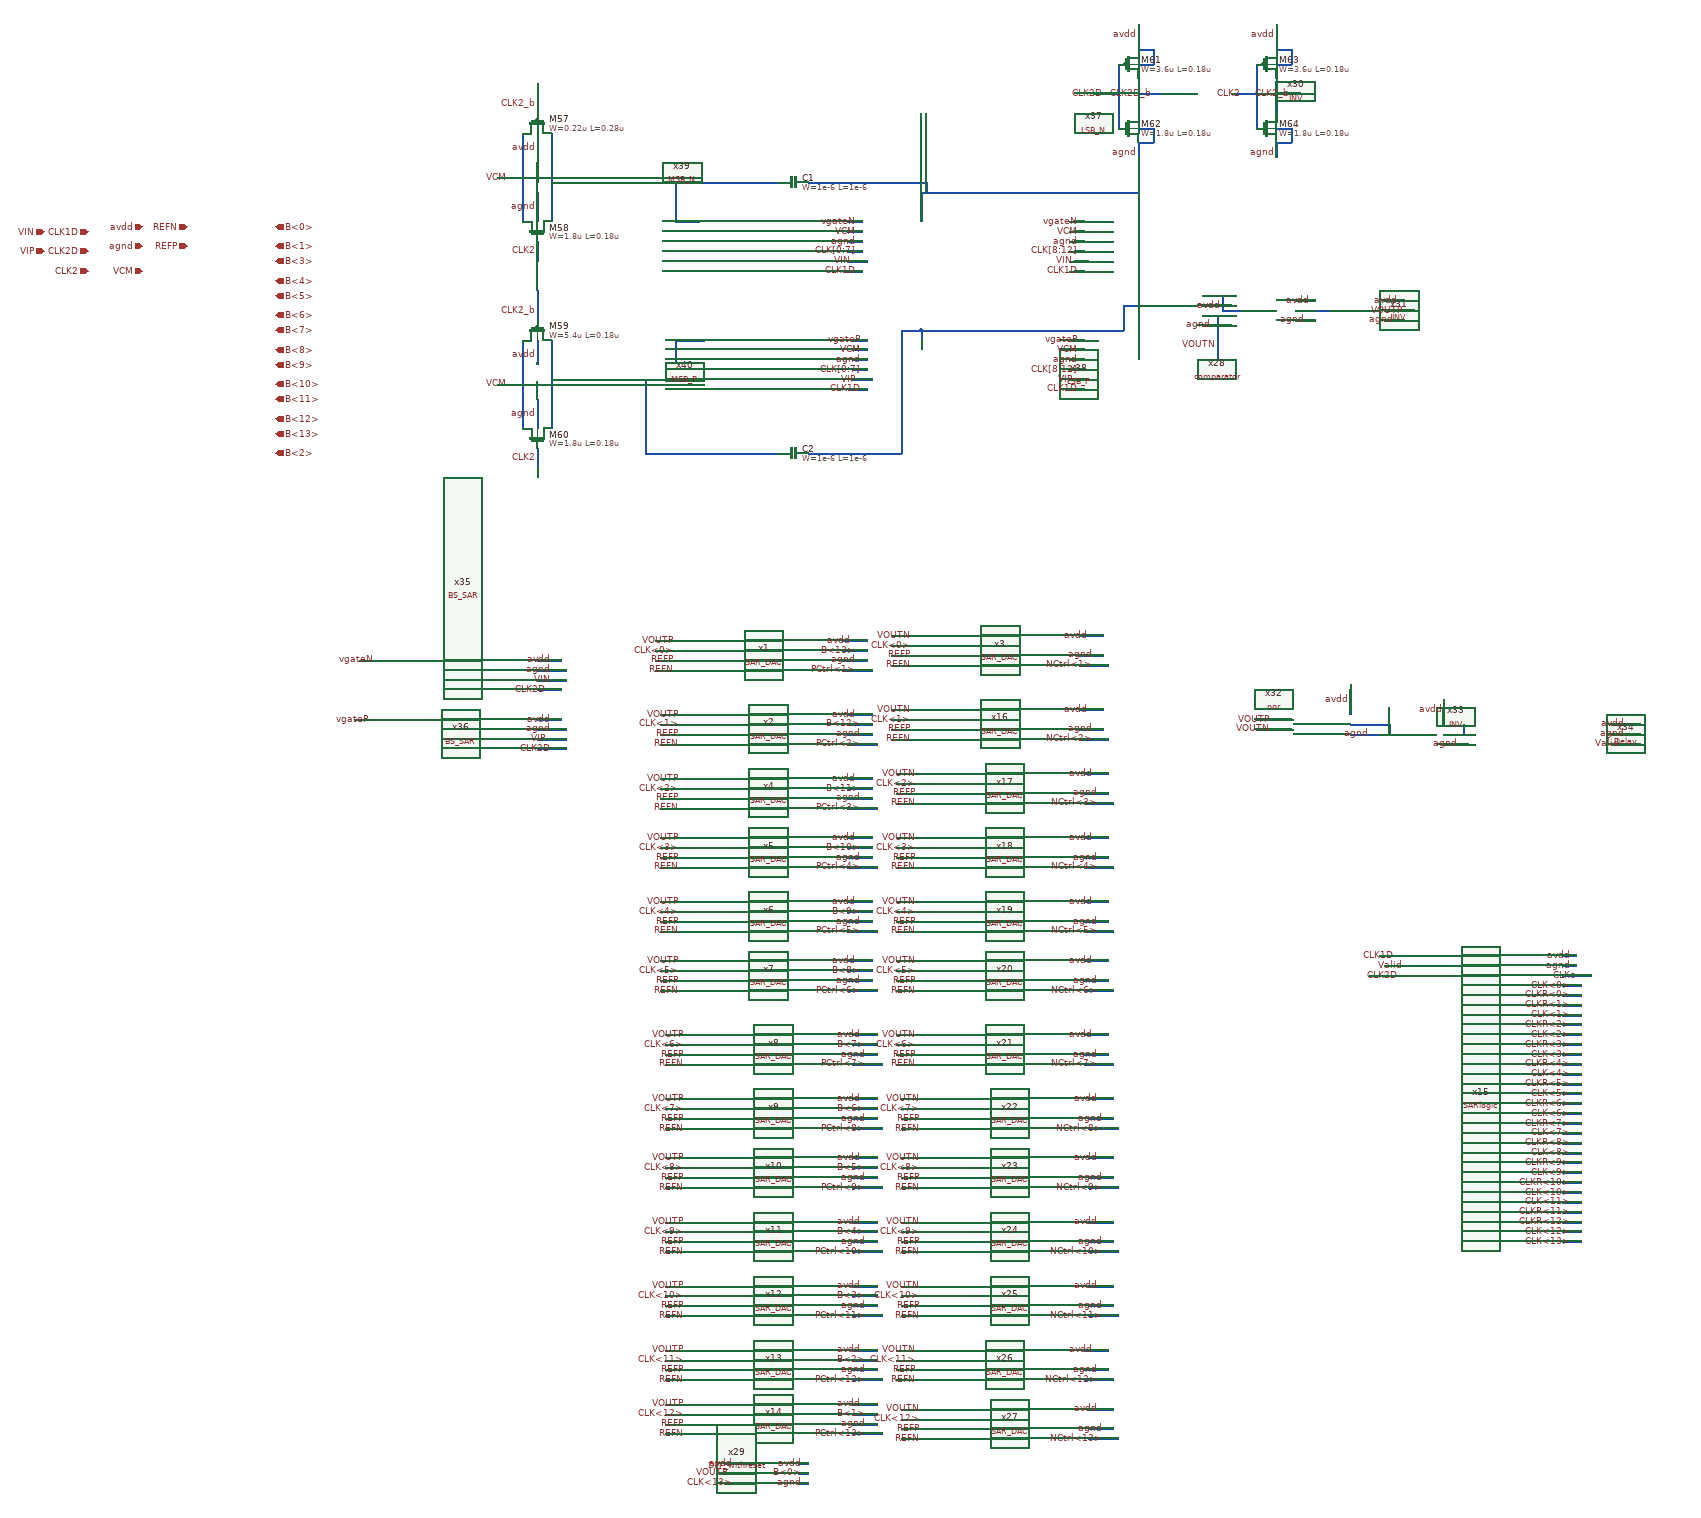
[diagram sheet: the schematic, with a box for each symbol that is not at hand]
v {xschem version=3.1.0 file_version=1.2
}
G {}
K {}
V {}
S {}
E {}
N 660 -670 710 -670 {
lab=avdd}
N 660 -630 710 -630 {
lab=agnd}
N 660 -610 720 -610 {
lab=PCtrl}
N 660 -650 710 -650 {
lab=B<13>}
N 280 -670 360 -670 {
lab=VOUTP}
N 280 -650 360 -650 {
lab=CLK<0>}
N 280 -630 360 -630 {
lab=REFP}
N 280 -610 360 -610 {
lab=REFN}
N 670 -520 720 -520 {
lab=avdd}
N 670 -480 720 -480 {
lab=agnd}
N 670 -460 730 -460 {
lab=PCtrl}
N 670 -500 720 -500 {
lab=B<12>}
N 290 -520 370 -520 {
lab=VOUTP}
N 290 -500 370 -500 {
lab=CLK<1>}
N 290 -480 370 -480 {
lab=REFP}
N 290 -460 370 -460 {
lab=REFN}
N 670 -390 720 -390 {
lab=avdd}
N 670 -350 720 -350 {
lab=agnd}
N 670 -330 730 -330 {
lab=PCtrl}
N 670 -370 720 -370 {
lab=B<11>}
N 290 -390 370 -390 {
lab=VOUTP}
N 290 -370 370 -370 {
lab=CLK<2>}
N 290 -350 370 -350 {
lab=REFP}
N 290 -330 370 -330 {
lab=REFN}
N 670 -270 720 -270 {
lab=avdd}
N 670 -230 720 -230 {
lab=agnd}
N 670 -210 730 -210 {
lab=PCtrl}
N 670 -250 720 -250 {
lab=B<10>}
N 290 -270 370 -270 {
lab=VOUTP}
N 290 -250 370 -250 {
lab=CLK<3>}
N 290 -230 370 -230 {
lab=REFP}
N 290 -210 370 -210 {
lab=REFN}
N 670 -140 720 -140 {
lab=avdd}
N 670 -100 720 -100 {
lab=agnd}
N 670 -80 730 -80 {
lab=PCtrl}
N 670 -120 720 -120 {
lab=B<9>}
N 290 -140 370 -140 {
lab=VOUTP}
N 290 -120 370 -120 {
lab=CLK<4>}
N 290 -100 370 -100 {
lab=REFP}
N 290 -80 370 -80 {
lab=REFN}
N 670 -20 720 -20 {
lab=avdd}
N 670 20 720 20 {
lab=agnd}
N 670 40 730 40 {
lab=PCtrl}
N 670 0 720 0 {
lab=B<8>}
N 290 -20 370 -20 {
lab=VOUTP}
N 290 0 370 0 {
lab=CLK<5>}
N 290 20 370 20 {
lab=REFP}
N 290 40 370 40 {
lab=REFN}
N 680 130 730 130 {
lab=avdd}
N 680 170 730 170 {
lab=agnd}
N 680 190 740 190 {
lab=PCtrl}
N 680 150 730 150 {
lab=B<7>}
N 300 130 380 130 {
lab=VOUTP}
N 300 150 380 150 {
lab=CLK<6>}
N 300 170 380 170 {
lab=REFP}
N 300 190 380 190 {
lab=REFN}
N 680 260 730 260 {
lab=avdd}
N 680 300 730 300 {
lab=agnd}
N 680 320 740 320 {
lab=PCtrl}
N 680 280 730 280 {
lab=B<6>}
N 300 260 380 260 {
lab=VOUTP}
N 300 280 380 280 {
lab=CLK<7>}
N 300 300 380 300 {
lab=REFP}
N 300 320 380 320 {
lab=REFN}
N 680 380 730 380 {
lab=avdd}
N 680 420 730 420 {
lab=agnd}
N 680 440 740 440 {
lab=PCtrl}
N 680 400 730 400 {
lab=B<5>}
N 300 380 380 380 {
lab=VOUTP}
N 300 400 380 400 {
lab=CLK<8>}
N 300 420 380 420 {
lab=REFP}
N 300 440 380 440 {
lab=REFN}
N 680 510 730 510 {
lab=avdd}
N 680 550 730 550 {
lab=agnd}
N 680 570 740 570 {
lab=PCtrl}
N 680 530 730 530 {
lab=B<4>}
N 300 510 380 510 {
lab=VOUTP}
N 300 530 380 530 {
lab=CLK<9>}
N 300 550 380 550 {
lab=REFP}
N 300 570 380 570 {
lab=REFN}
N 680 640 730 640 {
lab=avdd}
N 680 680 730 680 {
lab=agnd}
N 680 700 740 700 {
lab=PCtrl}
N 680 660 730 660 {
lab=B<3>}
N 300 640 380 640 {
lab=VOUTP}
N 300 660 380 660 {
lab=CLK<10>}
N 300 680 380 680 {
lab=REFP}
N 300 700 380 700 {
lab=REFN}
N 680 770 730 770 {
lab=avdd}
N 680 810 730 810 {
lab=agnd}
N 680 830 740 830 {
lab=PCtrl}
N 680 790 730 790 {
lab=B<2>}
N 300 770 380 770 {
lab=VOUTP}
N 300 790 380 790 {
lab=CLK<11>}
N 300 810 380 810 {
lab=REFP}
N 300 830 380 830 {
lab=REFN}
N 680 880 730 880 {
lab=avdd}
N 680 920 730 920 {
lab=agnd}
N 680 940 740 940 {
lab=PCtrl}
N 680 900 730 900 {
lab=B<1>}
N 300 880 380 880 {
lab=VOUTP}
N 300 900 380 900 {
lab=CLK<12>}
N 300 920 380 920 {
lab=REFP}
N 300 940 380 940 {
lab=REFN}
N 1140 -680 1190 -680 {
lab=avdd}
N 1140 -640 1190 -640 {
lab=agnd}
N 1140 -620 1200 -620 {
lab=NCtrl}
N 760 -680 840 -680 {
lab=VOUTN}
N 760 -660 840 -660 {
lab=CLK<0>}
N 760 -640 840 -640 {
lab=REFP}
N 760 -620 840 -620 {
lab=REFN}
N 1140 -530 1190 -530 {
lab=avdd}
N 1140 -490 1190 -490 {
lab=agnd}
N 1140 -470 1200 -470 {
lab=NCtrl}
N 760 -530 840 -530 {
lab=VOUTN}
N 760 -510 840 -510 {
lab=CLK<0>}
N 760 -490 840 -490 {
lab=REFP}
N 760 -470 840 -470 {
lab=REFN}
N 1150 -400 1200 -400 {
lab=avdd}
N 1150 -360 1200 -360 {
lab=agnd}
N 1150 -340 1210 -340 {
lab=NCtrl}
N 770 -400 850 -400 {
lab=VOUTN}
N 770 -380 850 -380 {
lab=CLK<0>}
N 770 -360 850 -360 {
lab=REFP}
N 770 -340 850 -340 {
lab=REFN}
N 1150 -270 1200 -270 {
lab=avdd}
N 1150 -230 1200 -230 {
lab=agnd}
N 1150 -210 1210 -210 {
lab=NCtrl}
N 770 -270 850 -270 {
lab=VOUTN}
N 770 -250 850 -250 {
lab=CLK<0>}
N 770 -230 850 -230 {
lab=REFP}
N 770 -210 850 -210 {
lab=REFN}
N 1150 -140 1200 -140 {
lab=avdd}
N 1150 -100 1200 -100 {
lab=agnd}
N 1150 -80 1210 -80 {
lab=NCtrl}
N 770 -140 850 -140 {
lab=VOUTN}
N 770 -120 850 -120 {
lab=CLK<0>}
N 770 -100 850 -100 {
lab=REFP}
N 770 -80 850 -80 {
lab=REFN}
N 1150 -20 1200 -20 {
lab=avdd}
N 1150 20 1200 20 {
lab=agnd}
N 1150 40 1210 40 {
lab=NCtrl}
N 770 -20 850 -20 {
lab=VOUTN}
N 770 0 850 0 {
lab=CLK<0>}
N 770 20 850 20 {
lab=REFP}
N 770 40 850 40 {
lab=REFN}
N 1150 130 1200 130 {
lab=avdd}
N 1150 170 1200 170 {
lab=agnd}
N 1150 190 1210 190 {
lab=NCtrl}
N 770 130 850 130 {
lab=VOUTN}
N 770 150 850 150 {
lab=CLK<0>}
N 770 170 850 170 {
lab=REFP}
N 770 190 850 190 {
lab=REFN}
N 1160 260 1210 260 {
lab=avdd}
N 1160 300 1210 300 {
lab=agnd}
N 1160 320 1220 320 {
lab=NCtrl}
N 780 260 860 260 {
lab=VOUTN}
N 780 280 860 280 {
lab=CLK<0>}
N 780 300 860 300 {
lab=REFP}
N 780 320 860 320 {
lab=REFN}
N 1160 380 1210 380 {
lab=avdd}
N 1160 420 1210 420 {
lab=agnd}
N 1160 440 1220 440 {
lab=NCtrl}
N 780 380 860 380 {
lab=VOUTN}
N 780 400 860 400 {
lab=CLK<0>}
N 780 420 860 420 {
lab=REFP}
N 780 440 860 440 {
lab=REFN}
N 1160 510 1210 510 {
lab=avdd}
N 1160 550 1210 550 {
lab=agnd}
N 1160 570 1220 570 {
lab=NCtrl}
N 780 510 860 510 {
lab=VOUTN}
N 780 530 860 530 {
lab=CLK<0>}
N 780 550 860 550 {
lab=REFP}
N 780 570 860 570 {
lab=REFN}
N 1160 640 1210 640 {
lab=avdd}
N 1160 680 1210 680 {
lab=agnd}
N 1160 700 1220 700 {
lab=NCtrl}
N 780 640 860 640 {
lab=VOUTN}
N 780 660 860 660 {
lab=CLK<0>}
N 780 680 860 680 {
lab=REFP}
N 780 700 860 700 {
lab=REFN}
N 1150 770 1200 770 {
lab=avdd}
N 1150 810 1200 810 {
lab=agnd}
N 1150 830 1210 830 {
lab=NCtrl}
N 770 770 850 770 {
lab=VOUTN}
N 770 790 850 790 {
lab=CLK<0>}
N 770 810 850 810 {
lab=REFP}
N 770 830 850 830 {
lab=REFN}
N 1160 890 1210 890 {
lab=avdd}
N 1160 930 1210 930 {
lab=agnd}
N 1160 950 1220 950 {
lab=NCtrl}
N 780 890 860 890 {
lab=VOUTN}
N 780 910 860 910 {
lab=CLK<0>}
N 780 930 860 930 {
lab=REFP}
N 780 950 860 950 {
lab=REFN}
N 420 1000 460 1000 {}
N 410 1020 460 1020 {}
N 420 1040 460 1040 {}
N 570 1000 590 1000 {}
N 570 1040 590 1040 {}
N 570 1020 590 1020 {}
N 2120 -30 2150 -30 {}
N 2120 -10 2150 -10 {}
N 1580 -1360 1620 -1360 {}
N 1580 -1320 1620 -1320 {}
N 1760 -1360 1800 -1360 {}
N 1760 -1320 1800 -1320 {}
N 1580 -1340 1650 -1340 {}
N 1390 -1350 1450 -1350 {}
N 1390 -1310 1450 -1310 {}
N 1390 -1330 1420 -1330 {}
N 1420 -1330 1420 -1240 {}
N 1390 -1370 1430 -1370 {}
N 1430 -1370 1430 -1340 {}
N 1430 -1340 1470 -1340 {}
N 1760 -1340 1820 -1340 {}
N 1690 -500 1770 -500 {}
N 1770 -500 1770 -480 {}
N 1880 -480 1920 -480 {}
N 1920 -500 1920 -480 {}
N 1690 -580 1690 -520 {}
N 1690 -480 1750 -480 {}
N 2220 -500 2280 -500 {}
N 2220 -480 2280 -480 {}
N 2220 -460 2280 -460 {}
N 1880 -550 1880 -500 {}
N 1880 -460 1930 -460 {}
N 1760 -10 1830 -10 {}
N 1750 -30 1830 -30 {}
N 1730 10 1830 10 {}
N 2120 10 2180 10 {}
N 40 -610 100 -610 {}
N 40 -630 90 -630 {}
N 40 -490 100 -490 {}
N 40 -510 90 -510 {}
N 40 -570 90 -570 {}
N 40 -450 100 -450 {}
N 40 -590 100 -590 {}
N 40 -470 100 -470 {}
N -320 -630 -260 -630 {}
N -330 -510 -260 -510 {}
N 1500 -510 1570 -510 {}
N 1500 -490 1570 -490 {}
N 70 -1700 70 -1520 {}
N 10 -1700 10 -1520 {}
N 40 -1700 40 -1650 {}
N 40 -1580 40 -1520 {}
N -40 -1610 10 -1610 {}
N 40 -1480 40 -1440 {}
N 40 -1800 40 -1740 {}
N 70 -1280 70 -1100 {}
N 10 -1280 10 -1100 {}
N 40 -1280 40 -1230 {}
N 40 -1160 40 -1100 {}
N -40 -1190 10 -1190 {}
N 40 -1060 40 -1020 {}
N 40 -1380 40 -1320 {}
N 70 -1200 320 -1200 {}
N 70 -1600 320 -1600 {}
N 1260 -1810 1260 -1740 {}
N 1220 -1840 1220 -1710 {}
N 1260 -1710 1290 -1710 {}
N 1290 -1710 1290 -1680 {}
N 1260 -1680 1290 -1680 {}
N 1260 -1680 1260 -1650 {}
N 1260 -1840 1290 -1840 {}
N 1290 -1870 1290 -1840 {}
N 1260 -1870 1290 -1870 {}
N 1260 -1920 1260 -1870 {}
N 1170 -1780 1220 -1780 {}
N 1260 -1780 1310 -1780 {}
N 1540 -1810 1540 -1740 {}
N 1500 -1840 1500 -1710 {}
N 1540 -1710 1570 -1710 {}
N 1570 -1710 1570 -1680 {}
N 1540 -1680 1570 -1680 {}
N 1540 -1680 1540 -1650 {}
N 1540 -1840 1570 -1840 {}
N 1570 -1870 1570 -1840 {}
N 1540 -1870 1570 -1870 {}
N 1540 -1920 1540 -1870 {}
N 1450 -1780 1500 -1780 {}
N 1540 -1780 1590 -1780 {}
N 2120 30 2160 30 {}
N 2120 50 2160 50 {}
N 2120 70 2160 70 {}
N 2120 90 2160 90 {}
N 2120 110 2160 110 {}
N 2120 130 2160 130 {}
N 2120 150 2160 150 {}
N 2120 170 2160 170 {}
N 2120 190 2160 190 {}
N 2120 210 2160 210 {}
N 2120 230 2160 230 {}
N 2120 250 2160 250 {}
N 2120 270 2160 270 {}
N 2120 290 2160 290 {}
N 2120 310 2160 310 {}
N 2120 330 2160 330 {}
N 2120 350 2160 350 {}
N 2120 370 2160 370 {}
N 2120 390 2160 390 {}
N 2120 410 2160 410 {}
N 2120 430 2160 430 {}
N 2120 450 2160 450 {}
N 2120 470 2160 470 {}
N 2120 490 2160 490 {}
N 2120 510 2160 510 {}
N 2120 530 2160 530 {}
N 2120 550 2160 550 {}
N 670 -1440 710 -1440 {}
N 670 -1500 700 -1500 {}
N 670 -1520 700 -1520 {}
N 670 -1480 700 -1480 {}
N 670 -1460 700 -1460 {}
N 670 -1420 700 -1420 {}
N 680 -1200 720 -1200 {}
N 680 -1260 710 -1260 {}
N 680 -1280 710 -1280 {}
N 680 -1240 710 -1240 {}
N 680 -1220 710 -1220 {}
N 680 -1180 710 -1180 {}
N 320 -1600 320 -1520 {}
N 320 -1520 370 -1520 {}
N 320 -1280 320 -1200 {}
N 320 -1280 380 -1280 {}
N 820 -1580 820 -1520 {}
N 820 -1580 1260 -1580 {}
N 1260 -1580 1260 -1370 {}
N 820 -1300 820 -1280 {}
N 820 -1300 1230 -1300 {}
N 1230 -1350 1230 -1300 {}
N 1230 -1350 1260 -1350 {}
N 1120 -1200 1160 -1200 {}
N 1120 -1260 1150 -1260 {}
N 1120 -1280 1150 -1280 {}
N 1120 -1240 1150 -1240 {}
N 1120 -1220 1150 -1220 {}
N 1120 -1180 1150 -1180 {}
N 1120 -1440 1160 -1440 {}
N 1120 -1500 1150 -1500 {}
N 1120 -1520 1150 -1520 {}
N 1120 -1480 1150 -1480 {}
N 1120 -1460 1150 -1460 {}
N 1120 -1420 1150 -1420 {}
N 260 -1200 260 -1050 {}
N 260 -1050 530 -1050 {}
N 780 -1300 780 -1050 {}
N 780 -1300 820 -1300 {}
N 320 -1600 530 -1600 {}
N 590 -1600 830 -1600 {}
N 830 -1600 830 -1580 {}
N 590 -1050 780 -1050 {}
C {SAR_DAC.sym} 510 -640 0 0 {name=x1}
C {lab_pin.sym} 320 -630 0 0 {name=p1 sig_type=std_logic lab=REFP}
C {lab_pin.sym} 320 -610 0 0 {name=p2 sig_type=std_logic lab=REFN}
C {lab_pin.sym} 320 -650 0 0 {name=p3 sig_type=std_logic lab=CLK<0>}
C {lab_pin.sym} 320 -670 0 0 {name=p4 sig_type=std_logic lab=VOUTP}
C {lab_pin.sym} 690 -610 0 0 {name=p5 sig_type=std_logic lab=PCtrl<1>}
C {lab_pin.sym} 690 -630 0 0 {name=p6 sig_type=std_logic lab=agnd}
C {lab_pin.sym} 680 -670 0 0 {name=p7 sig_type=std_logic lab=avdd}
C {lab_pin.sym} 690 -650 0 0 {name=p8 sig_type=std_logic lab=B<13>}
C {SAR_DAC.sym} 520 -490 0 0 {name=x2}
C {lab_pin.sym} 330 -480 0 0 {name=p9 sig_type=std_logic lab=REFP}
C {lab_pin.sym} 330 -460 0 0 {name=p10 sig_type=std_logic lab=REFN}
C {lab_pin.sym} 330 -500 0 0 {name=p11 sig_type=std_logic lab=CLK<1>}
C {lab_pin.sym} 330 -520 0 0 {name=p12 sig_type=std_logic lab=VOUTP}
C {lab_pin.sym} 700 -460 0 0 {name=p13 sig_type=std_logic lab=PCtrl<2>}
C {lab_pin.sym} 700 -480 0 0 {name=p14 sig_type=std_logic lab=agnd}
C {lab_pin.sym} 690 -520 0 0 {name=p15 sig_type=std_logic lab=avdd}
C {lab_pin.sym} 700 -500 0 0 {name=p16 sig_type=std_logic lab=B<12>}
C {lab_pin.sym} 330 -350 0 0 {name=p17 sig_type=std_logic lab=REFP}
C {lab_pin.sym} 330 -330 0 0 {name=p18 sig_type=std_logic lab=REFN}
C {lab_pin.sym} 330 -370 0 0 {name=p19 sig_type=std_logic lab=CLK<2>}
C {lab_pin.sym} 330 -390 0 0 {name=p20 sig_type=std_logic lab=VOUTP}
C {lab_pin.sym} 700 -330 0 0 {name=p21 sig_type=std_logic lab=PCtrl<3>}
C {lab_pin.sym} 700 -350 0 0 {name=p22 sig_type=std_logic lab=agnd}
C {lab_pin.sym} 690 -390 0 0 {name=p23 sig_type=std_logic lab=avdd}
C {lab_pin.sym} 700 -370 0 0 {name=p24 sig_type=std_logic lab=B<11>}
C {SAR_DAC.sym} 520 -240 0 0 {name=x5}
C {lab_pin.sym} 330 -230 0 0 {name=p25 sig_type=std_logic lab=REFP}
C {lab_pin.sym} 330 -210 0 0 {name=p26 sig_type=std_logic lab=REFN}
C {lab_pin.sym} 330 -250 0 0 {name=p27 sig_type=std_logic lab=CLK<3>}
C {lab_pin.sym} 330 -270 0 0 {name=p28 sig_type=std_logic lab=VOUTP}
C {lab_pin.sym} 700 -210 0 0 {name=p29 sig_type=std_logic lab=PCtrl<4>}
C {lab_pin.sym} 700 -230 0 0 {name=p30 sig_type=std_logic lab=agnd}
C {lab_pin.sym} 690 -270 0 0 {name=p31 sig_type=std_logic lab=avdd}
C {lab_pin.sym} 700 -250 0 0 {name=p32 sig_type=std_logic lab=B<10>}
C {SAR_DAC.sym} 520 -110 0 0 {name=x6}
C {lab_pin.sym} 330 -100 0 0 {name=p33 sig_type=std_logic lab=REFP}
C {lab_pin.sym} 330 -80 0 0 {name=p34 sig_type=std_logic lab=REFN}
C {lab_pin.sym} 330 -120 0 0 {name=p35 sig_type=std_logic lab=CLK<4>}
C {lab_pin.sym} 330 -140 0 0 {name=p36 sig_type=std_logic lab=VOUTP}
C {lab_pin.sym} 700 -80 0 0 {name=p37 sig_type=std_logic lab=PCtrl<5>}
C {lab_pin.sym} 700 -100 0 0 {name=p38 sig_type=std_logic lab=agnd}
C {lab_pin.sym} 690 -140 0 0 {name=p39 sig_type=std_logic lab=avdd}
C {lab_pin.sym} 700 -120 0 0 {name=p40 sig_type=std_logic lab=B<9>}
C {SAR_DAC.sym} 520 10 0 0 {name=x7}
C {lab_pin.sym} 330 20 0 0 {name=p41 sig_type=std_logic lab=REFP}
C {lab_pin.sym} 330 40 0 0 {name=p42 sig_type=std_logic lab=REFN}
C {lab_pin.sym} 330 0 0 0 {name=p43 sig_type=std_logic lab=CLK<5>}
C {lab_pin.sym} 330 -20 0 0 {name=p44 sig_type=std_logic lab=VOUTP}
C {lab_pin.sym} 700 40 0 0 {name=p45 sig_type=std_logic lab=PCtrl<6>}
C {lab_pin.sym} 700 20 0 0 {name=p46 sig_type=std_logic lab=agnd}
C {lab_pin.sym} 690 -20 0 0 {name=p47 sig_type=std_logic lab=avdd}
C {lab_pin.sym} 700 0 0 0 {name=p48 sig_type=std_logic lab=B<8>}
C {SAR_DAC.sym} 530 160 0 0 {name=x8}
C {lab_pin.sym} 340 170 0 0 {name=p49 sig_type=std_logic lab=REFP}
C {lab_pin.sym} 340 190 0 0 {name=p50 sig_type=std_logic lab=REFN}
C {lab_pin.sym} 340 150 0 0 {name=p51 sig_type=std_logic lab=CLK<6>}
C {lab_pin.sym} 340 130 0 0 {name=p52 sig_type=std_logic lab=VOUTP}
C {lab_pin.sym} 710 190 0 0 {name=p53 sig_type=std_logic lab=PCtrl<7>}
C {lab_pin.sym} 710 170 0 0 {name=p54 sig_type=std_logic lab=agnd}
C {lab_pin.sym} 700 130 0 0 {name=p55 sig_type=std_logic lab=avdd}
C {lab_pin.sym} 710 150 0 0 {name=p56 sig_type=std_logic lab=B<7>}
C {SAR_DAC.sym} 530 290 0 0 {name=x9}
C {lab_pin.sym} 340 300 0 0 {name=p57 sig_type=std_logic lab=REFP}
C {lab_pin.sym} 340 320 0 0 {name=p58 sig_type=std_logic lab=REFN}
C {lab_pin.sym} 340 280 0 0 {name=p59 sig_type=std_logic lab=CLK<7>}
C {lab_pin.sym} 340 260 0 0 {name=p60 sig_type=std_logic lab=VOUTP}
C {lab_pin.sym} 710 320 0 0 {name=p61 sig_type=std_logic lab=PCtrl<8>}
C {lab_pin.sym} 710 300 0 0 {name=p62 sig_type=std_logic lab=agnd}
C {lab_pin.sym} 700 260 0 0 {name=p63 sig_type=std_logic lab=avdd}
C {lab_pin.sym} 710 280 0 0 {name=p64 sig_type=std_logic lab=B<6>}
C {SAR_DAC.sym} 530 410 0 0 {name=x10}
C {lab_pin.sym} 340 420 0 0 {name=p65 sig_type=std_logic lab=REFP}
C {lab_pin.sym} 340 440 0 0 {name=p66 sig_type=std_logic lab=REFN}
C {lab_pin.sym} 340 400 0 0 {name=p67 sig_type=std_logic lab=CLK<8>}
C {lab_pin.sym} 340 380 0 0 {name=p68 sig_type=std_logic lab=VOUTP}
C {lab_pin.sym} 710 440 0 0 {name=p69 sig_type=std_logic lab=PCtrl<9>}
C {lab_pin.sym} 710 420 0 0 {name=p70 sig_type=std_logic lab=agnd}
C {lab_pin.sym} 700 380 0 0 {name=p71 sig_type=std_logic lab=avdd}
C {lab_pin.sym} 710 400 0 0 {name=p72 sig_type=std_logic lab=B<5>}
C {SAR_DAC.sym} 530 540 0 0 {name=x11}
C {lab_pin.sym} 340 550 0 0 {name=p73 sig_type=std_logic lab=REFP}
C {lab_pin.sym} 340 570 0 0 {name=p74 sig_type=std_logic lab=REFN}
C {lab_pin.sym} 340 530 0 0 {name=p75 sig_type=std_logic lab=CLK<9>}
C {lab_pin.sym} 340 510 0 0 {name=p76 sig_type=std_logic lab=VOUTP}
C {lab_pin.sym} 710 570 0 0 {name=p77 sig_type=std_logic lab=PCtrl<10>}
C {lab_pin.sym} 710 550 0 0 {name=p78 sig_type=std_logic lab=agnd}
C {lab_pin.sym} 700 510 0 0 {name=p79 sig_type=std_logic lab=avdd}
C {lab_pin.sym} 710 530 0 0 {name=p80 sig_type=std_logic lab=B<4>}
C {SAR_DAC.sym} 530 670 0 0 {name=x12}
C {lab_pin.sym} 340 680 0 0 {name=p81 sig_type=std_logic lab=REFP}
C {lab_pin.sym} 340 700 0 0 {name=p82 sig_type=std_logic lab=REFN}
C {lab_pin.sym} 340 660 0 0 {name=p83 sig_type=std_logic lab=CLK<10>}
C {lab_pin.sym} 340 640 0 0 {name=p84 sig_type=std_logic lab=VOUTP}
C {lab_pin.sym} 710 700 0 0 {name=p85 sig_type=std_logic lab=PCtrl<11>}
C {lab_pin.sym} 710 680 0 0 {name=p86 sig_type=std_logic lab=agnd}
C {lab_pin.sym} 700 640 0 0 {name=p87 sig_type=std_logic lab=avdd}
C {lab_pin.sym} 710 660 0 0 {name=p88 sig_type=std_logic lab=B<3>}
C {SAR_DAC.sym} 530 800 0 0 {name=x13}
C {lab_pin.sym} 340 810 0 0 {name=p89 sig_type=std_logic lab=REFP}
C {lab_pin.sym} 340 830 0 0 {name=p90 sig_type=std_logic lab=REFN}
C {lab_pin.sym} 340 790 0 0 {name=p91 sig_type=std_logic lab=CLK<11>}
C {lab_pin.sym} 340 770 0 0 {name=p92 sig_type=std_logic lab=VOUTP}
C {lab_pin.sym} 710 830 0 0 {name=p93 sig_type=std_logic lab=PCtrl<12>}
C {lab_pin.sym} 710 810 0 0 {name=p94 sig_type=std_logic lab=agnd}
C {lab_pin.sym} 700 770 0 0 {name=p95 sig_type=std_logic lab=avdd}
C {lab_pin.sym} 710 790 0 0 {name=p96 sig_type=std_logic lab=B<2>}
C {SAR_DAC.sym} 530 910 0 0 {name=x14}
C {lab_pin.sym} 340 920 0 0 {name=p97 sig_type=std_logic lab=REFP}
C {lab_pin.sym} 340 940 0 0 {name=p98 sig_type=std_logic lab=REFN}
C {lab_pin.sym} 340 900 0 0 {name=p99 sig_type=std_logic lab=CLK<12>}
C {lab_pin.sym} 340 880 0 0 {name=p100 sig_type=std_logic lab=VOUTP}
C {lab_pin.sym} 710 940 0 0 {name=p101 sig_type=std_logic lab=PCtrl<13>}
C {lab_pin.sym} 710 920 0 0 {name=p102 sig_type=std_logic lab=agnd}
C {lab_pin.sym} 700 880 0 0 {name=p103 sig_type=std_logic lab=avdd}
C {lab_pin.sym} 710 900 0 0 {name=p104 sig_type=std_logic lab=B<1>}
C {SAR_DAC.sym} 520 -360 0 0 {name=x4}
C {SAR_DAC.sym} 990 -650 0 0 {name=x3}
C {lab_pin.sym} 800 -640 0 0 {name=p113 sig_type=std_logic lab=REFP}
C {lab_pin.sym} 800 -620 0 0 {name=p114 sig_type=std_logic lab=REFN}
C {lab_pin.sym} 800 -660 0 0 {name=p115 sig_type=std_logic lab=CLK<0>}
C {lab_pin.sym} 800 -680 0 0 {name=p116 sig_type=std_logic lab=VOUTN}
C {lab_pin.sym} 1170 -620 0 0 {name=p117 sig_type=std_logic lab=NCtrl<1>}
C {lab_pin.sym} 1170 -640 0 0 {name=p118 sig_type=std_logic lab=agnd}
C {lab_pin.sym} 1160 -680 0 0 {name=p119 sig_type=std_logic lab=avdd}
C {noconn.sym} 1140 -660 2 0 {name=l1}
C {SAR_DAC.sym} 990 -500 0 0 {name=x16}
C {lab_pin.sym} 800 -490 0 0 {name=p120 sig_type=std_logic lab=REFP}
C {lab_pin.sym} 800 -470 0 0 {name=p121 sig_type=std_logic lab=REFN}
C {lab_pin.sym} 800 -510 0 0 {name=p122 sig_type=std_logic lab=CLK<1>}
C {lab_pin.sym} 800 -530 0 0 {name=p123 sig_type=std_logic lab=VOUTN}
C {lab_pin.sym} 1170 -470 0 0 {name=p124 sig_type=std_logic lab=NCtrl<2>}
C {lab_pin.sym} 1170 -490 0 0 {name=p125 sig_type=std_logic lab=agnd}
C {lab_pin.sym} 1160 -530 0 0 {name=p126 sig_type=std_logic lab=avdd}
C {noconn.sym} 1140 -510 2 0 {name=l2}
C {SAR_DAC.sym} 1000 -370 0 0 {name=x17}
C {lab_pin.sym} 810 -360 0 0 {name=p127 sig_type=std_logic lab=REFP}
C {lab_pin.sym} 810 -340 0 0 {name=p128 sig_type=std_logic lab=REFN}
C {lab_pin.sym} 810 -380 0 0 {name=p129 sig_type=std_logic lab=CLK<2>}
C {lab_pin.sym} 810 -400 0 0 {name=p130 sig_type=std_logic lab=VOUTN}
C {lab_pin.sym} 1180 -340 0 0 {name=p131 sig_type=std_logic lab=NCtrl<3>}
C {lab_pin.sym} 1180 -360 0 0 {name=p132 sig_type=std_logic lab=agnd}
C {lab_pin.sym} 1170 -400 0 0 {name=p133 sig_type=std_logic lab=avdd}
C {noconn.sym} 1150 -380 2 0 {name=l3}
C {SAR_DAC.sym} 1000 -240 0 0 {name=x18}
C {lab_pin.sym} 810 -230 0 0 {name=p134 sig_type=std_logic lab=REFP}
C {lab_pin.sym} 810 -210 0 0 {name=p135 sig_type=std_logic lab=REFN}
C {lab_pin.sym} 810 -250 0 0 {name=p136 sig_type=std_logic lab=CLK<3>}
C {lab_pin.sym} 810 -270 0 0 {name=p137 sig_type=std_logic lab=VOUTN}
C {lab_pin.sym} 1180 -210 0 0 {name=p138 sig_type=std_logic lab=NCtrl<4>}
C {lab_pin.sym} 1180 -230 0 0 {name=p139 sig_type=std_logic lab=agnd}
C {lab_pin.sym} 1170 -270 0 0 {name=p140 sig_type=std_logic lab=avdd}
C {noconn.sym} 1150 -250 2 0 {name=l4}
C {SAR_DAC.sym} 1000 -110 0 0 {name=x19}
C {lab_pin.sym} 810 -100 0 0 {name=p141 sig_type=std_logic lab=REFP}
C {lab_pin.sym} 810 -80 0 0 {name=p142 sig_type=std_logic lab=REFN}
C {lab_pin.sym} 810 -120 0 0 {name=p143 sig_type=std_logic lab=CLK<4>}
C {lab_pin.sym} 810 -140 0 0 {name=p144 sig_type=std_logic lab=VOUTN}
C {lab_pin.sym} 1180 -80 0 0 {name=p145 sig_type=std_logic lab=NCtrl<5>}
C {lab_pin.sym} 1180 -100 0 0 {name=p146 sig_type=std_logic lab=agnd}
C {lab_pin.sym} 1170 -140 0 0 {name=p147 sig_type=std_logic lab=avdd}
C {noconn.sym} 1150 -120 2 0 {name=l5}
C {SAR_DAC.sym} 1000 10 0 0 {name=x20}
C {lab_pin.sym} 810 20 0 0 {name=p148 sig_type=std_logic lab=REFP}
C {lab_pin.sym} 810 40 0 0 {name=p149 sig_type=std_logic lab=REFN}
C {lab_pin.sym} 810 0 0 0 {name=p150 sig_type=std_logic lab=CLK<5>}
C {lab_pin.sym} 810 -20 0 0 {name=p151 sig_type=std_logic lab=VOUTN}
C {lab_pin.sym} 1180 40 0 0 {name=p152 sig_type=std_logic lab=NCtrl<6>}
C {lab_pin.sym} 1180 20 0 0 {name=p153 sig_type=std_logic lab=agnd}
C {lab_pin.sym} 1170 -20 0 0 {name=p154 sig_type=std_logic lab=avdd}
C {noconn.sym} 1150 0 2 0 {name=l6}
C {SAR_DAC.sym} 1000 160 0 0 {name=x21}
C {lab_pin.sym} 810 170 0 0 {name=p155 sig_type=std_logic lab=REFP}
C {lab_pin.sym} 810 190 0 0 {name=p156 sig_type=std_logic lab=REFN}
C {lab_pin.sym} 810 150 0 0 {name=p157 sig_type=std_logic lab=CLK<6>}
C {lab_pin.sym} 810 130 0 0 {name=p158 sig_type=std_logic lab=VOUTN}
C {lab_pin.sym} 1180 190 0 0 {name=p159 sig_type=std_logic lab=NCtrl<7>}
C {lab_pin.sym} 1180 170 0 0 {name=p160 sig_type=std_logic lab=agnd}
C {lab_pin.sym} 1170 130 0 0 {name=p161 sig_type=std_logic lab=avdd}
C {noconn.sym} 1150 150 2 0 {name=l7}
C {SAR_DAC.sym} 1010 290 0 0 {name=x22}
C {lab_pin.sym} 820 300 0 0 {name=p162 sig_type=std_logic lab=REFP}
C {lab_pin.sym} 820 320 0 0 {name=p163 sig_type=std_logic lab=REFN}
C {lab_pin.sym} 820 280 0 0 {name=p164 sig_type=std_logic lab=CLK<7>}
C {lab_pin.sym} 820 260 0 0 {name=p165 sig_type=std_logic lab=VOUTN}
C {lab_pin.sym} 1190 320 0 0 {name=p166 sig_type=std_logic lab=NCtrl<8>}
C {lab_pin.sym} 1190 300 0 0 {name=p167 sig_type=std_logic lab=agnd}
C {lab_pin.sym} 1180 260 0 0 {name=p168 sig_type=std_logic lab=avdd}
C {noconn.sym} 1160 280 2 0 {name=l8}
C {SAR_DAC.sym} 1010 410 0 0 {name=x23}
C {lab_pin.sym} 820 420 0 0 {name=p169 sig_type=std_logic lab=REFP}
C {lab_pin.sym} 820 440 0 0 {name=p170 sig_type=std_logic lab=REFN}
C {lab_pin.sym} 820 400 0 0 {name=p171 sig_type=std_logic lab=CLK<8>}
C {lab_pin.sym} 820 380 0 0 {name=p172 sig_type=std_logic lab=VOUTN}
C {lab_pin.sym} 1190 440 0 0 {name=p173 sig_type=std_logic lab=NCtrl<9>}
C {lab_pin.sym} 1190 420 0 0 {name=p174 sig_type=std_logic lab=agnd}
C {lab_pin.sym} 1180 380 0 0 {name=p175 sig_type=std_logic lab=avdd}
C {noconn.sym} 1160 400 2 0 {name=l9}
C {SAR_DAC.sym} 1010 540 0 0 {name=x24}
C {lab_pin.sym} 820 550 0 0 {name=p176 sig_type=std_logic lab=REFP}
C {lab_pin.sym} 820 570 0 0 {name=p177 sig_type=std_logic lab=REFN}
C {lab_pin.sym} 820 530 0 0 {name=p178 sig_type=std_logic lab=CLK<9>}
C {lab_pin.sym} 820 510 0 0 {name=p179 sig_type=std_logic lab=VOUTN}
C {lab_pin.sym} 1190 570 0 0 {name=p180 sig_type=std_logic lab=NCtrl<10>}
C {lab_pin.sym} 1190 550 0 0 {name=p181 sig_type=std_logic lab=agnd}
C {lab_pin.sym} 1180 510 0 0 {name=p182 sig_type=std_logic lab=avdd}
C {noconn.sym} 1160 530 2 0 {name=l10}
C {SAR_DAC.sym} 1010 670 0 0 {name=x25}
C {lab_pin.sym} 820 680 0 0 {name=p183 sig_type=std_logic lab=REFP}
C {lab_pin.sym} 820 700 0 0 {name=p184 sig_type=std_logic lab=REFN}
C {lab_pin.sym} 820 660 0 0 {name=p185 sig_type=std_logic lab=CLK<10>}
C {lab_pin.sym} 820 640 0 0 {name=p186 sig_type=std_logic lab=VOUTN}
C {lab_pin.sym} 1190 700 0 0 {name=p187 sig_type=std_logic lab=NCtrl<11>}
C {lab_pin.sym} 1190 680 0 0 {name=p188 sig_type=std_logic lab=agnd}
C {lab_pin.sym} 1180 640 0 0 {name=p189 sig_type=std_logic lab=avdd}
C {noconn.sym} 1160 660 2 0 {name=l11}
C {SAR_DAC.sym} 1000 800 0 0 {name=x26}
C {lab_pin.sym} 810 810 0 0 {name=p190 sig_type=std_logic lab=REFP}
C {lab_pin.sym} 810 830 0 0 {name=p191 sig_type=std_logic lab=REFN}
C {lab_pin.sym} 810 790 0 0 {name=p192 sig_type=std_logic lab=CLK<11>}
C {lab_pin.sym} 810 770 0 0 {name=p193 sig_type=std_logic lab=VOUTN}
C {lab_pin.sym} 1180 830 0 0 {name=p194 sig_type=std_logic lab=NCtrl<12>}
C {lab_pin.sym} 1180 810 0 0 {name=p195 sig_type=std_logic lab=agnd}
C {lab_pin.sym} 1170 770 0 0 {name=p196 sig_type=std_logic lab=avdd}
C {noconn.sym} 1150 790 2 0 {name=l12}
C {SAR_DAC.sym} 1010 920 0 0 {name=x27}
C {lab_pin.sym} 820 930 0 0 {name=p197 sig_type=std_logic lab=REFP}
C {lab_pin.sym} 820 950 0 0 {name=p198 sig_type=std_logic lab=REFN}
C {lab_pin.sym} 820 910 0 0 {name=p199 sig_type=std_logic lab=CLK<12>}
C {lab_pin.sym} 820 890 0 0 {name=p200 sig_type=std_logic lab=VOUTN}
C {lab_pin.sym} 1190 950 0 0 {name=p201 sig_type=std_logic lab=NCtrl<13>}
C {lab_pin.sym} 1190 930 0 0 {name=p202 sig_type=std_logic lab=agnd}
C {lab_pin.sym} 1180 890 0 0 {name=p203 sig_type=std_logic lab=avdd}
C {noconn.sym} 1160 910 2 0 {name=l13}
C {DFF_withreset.sym} 510 1020 0 0 {name=x29}
C {lab_pin.sym} 440 1000 0 0 {name=p211 sig_type=std_logic lab=avdd}
C {lab_pin.sym} 430 1020 0 0 {name=p212 sig_type=std_logic lab=VOUTP}
C {lab_pin.sym} 440 1040 0 0 {name=p105 sig_type=std_logic lab=CLK<13>}
C {lab_pin.sym} 580 1000 0 0 {name=p106 sig_type=std_logic lab=avdd}
C {lab_pin.sym} 580 1040 0 0 {name=p107 sig_type=std_logic lab=agnd}
C {lab_pin.sym} 580 1020 0 0 {name=p108 sig_type=std_logic lab=B<0>}
C {lab_pin.sym} 2140 -30 0 0 {name=p109 sig_type=std_logic lab=avdd}
C {lab_pin.sym} 2140 -10 0 0 {name=p110 sig_type=std_logic lab=agnd}
C {comparator.sym} 1370 -1340 0 0 {name=x28}
C {INV.sym} 1530 -1340 0 0 {name=x30}
C {lab_pin.sym} 1610 -1360 0 0 {name=p111 sig_type=std_logic lab=avdd}
C {lab_pin.sym} 1600 -1320 0 0 {name=p112 sig_type=std_logic lab=agnd}
C {INV.sym} 1710 -1340 0 0 {name=x31}
C {lab_pin.sym} 1790 -1360 0 0 {name=p204 sig_type=std_logic lab=avdd}
C {lab_pin.sym} 1780 -1320 0 0 {name=p205 sig_type=std_logic lab=agnd}
C {lab_pin.sym} 1430 -1350 0 0 {name=p206 sig_type=std_logic lab=avdd}
C {lab_pin.sym} 1410 -1310 0 0 {name=p207 sig_type=std_logic lab=agnd}
C {lab_pin.sym} 1420 -1270 0 0 {name=p208 sig_type=std_logic lab=VOUTN}
C {lab_pin.sym} 1800 -1340 0 0 {name=p209 sig_type=std_logic lab=VOUTP}
C {nor.sym} 1630 -500 0 0 {name=x32}
C {INV.sym} 1830 -480 0 0 {name=x33}
C {Delay.sym} 2070 -480 0 0 {name=x34}
C {lab_pin.sym} 1690 -550 0 0 {name=p210 sig_type=std_logic lab=avdd}
C {lab_pin.sym} 1730 -480 0 0 {name=p213 sig_type=std_logic lab=agnd}
C {lab_pin.sym} 2250 -500 0 0 {name=p214 sig_type=std_logic lab=avdd}
C {lab_pin.sym} 2250 -480 0 0 {name=p215 sig_type=std_logic lab=agnd}
C {lab_pin.sym} 1880 -530 0 0 {name=p216 sig_type=std_logic lab=avdd}
C {lab_pin.sym} 1910 -460 0 0 {name=p217 sig_type=std_logic lab=agnd}
C {lab_pin.sym} 2240 -460 0 0 {name=p218 sig_type=std_logic lab=Valid}
C {lab_pin.sym} 1800 -10 0 0 {name=p219 sig_type=std_logic lab=Valid}
C {lab_pin.sym} 1780 -30 0 0 {name=p220 sig_type=std_logic lab=CLK1D}
C {lab_pin.sym} 1790 10 0 0 {name=p221 sig_type=std_logic lab=CLK2D}
C {lab_pin.sym} 2150 10 0 0 {name=p222 sig_type=std_logic lab=CLKc}
C {BS_SAR.sym} -110 -600 0 0 {name=x35}
C {lab_pin.sym} 70 -630 0 0 {name=p281 sig_type=std_logic lab=avdd}
C {lab_pin.sym} 70 -610 0 0 {name=p282 sig_type=std_logic lab=agnd}
C {BS_SAR.sym} -110 -480 0 0 {name=x36}
C {lab_pin.sym} 70 -510 0 0 {name=p353 sig_type=std_logic lab=avdd}
C {lab_pin.sym} 70 -490 0 0 {name=p354 sig_type=std_logic lab=agnd}
C {lab_pin.sym} 60 -570 0 0 {name=p355 sig_type=std_logic lab=CLK2D}
C {lab_pin.sym} 70 -450 0 0 {name=p356 sig_type=std_logic lab=CLK2D}
C {lab_pin.sym} 70 -590 0 0 {name=p357 sig_type=std_logic lab=VIN}
C {lab_pin.sym} 60 -470 0 0 {name=p358 sig_type=std_logic lab=VIP}
C {lab_pin.sym} -290 -630 0 0 {name=p359 sig_type=std_logic lab=vgateN}
C {lab_pin.sym} -300 -510 0 0 {name=p360 sig_type=std_logic lab=vgateP}
C {lab_pin.sym} 1530 -510 0 0 {name=p361 sig_type=std_logic lab=VOUTP}
C {lab_pin.sym} 1530 -490 0 0 {name=p362 sig_type=std_logic lab=VOUTN}
C {pfet_03v3.sym} 40 -1720 1 0 {name=M57
L=0.28u
W=0.22u
nf=1
m=1
ad="'int((nf+1)/2) * W/nf * 0.18u'"
pd="'2*int((nf+1)/2) * (W/nf + 0.18u)'"
as="'int((nf+2)/2) * W/nf * 0.18u'"
ps="'2*int((nf+2)/2) * (W/nf + 0.18u)'"
nrd="'0.18u / W'" nrs="'0.18u / W'"
sa=0 sb=0 sd=0
model=pfet_03v3
spiceprefix=X
}
C {nfet_03v3.sym} 40 -1500 3 0 {name=M58
L=0.18u
W=1.8u
nf=1
m=1
ad="'int((nf+1)/2) * W/nf * 0.18u'"
pd="'2*int((nf+1)/2) * (W/nf + 0.18u)'"
as="'int((nf+2)/2) * W/nf * 0.18u'"
ps="'2*int((nf+2)/2) * (W/nf + 0.18u)'"
nrd="'0.18u / W'" nrs="'0.18u / W'"
sa=0 sb=0 sd=0
model=nfet_03v3
spiceprefix=X
}
C {lab_pin.sym} 40 -1670 0 0 {name=p363 sig_type=std_logic lab=avdd}
C {lab_pin.sym} 40 -1550 0 0 {name=p364 sig_type=std_logic lab=agnd}
C {lab_pin.sym} -20 -1610 0 0 {name=p365 sig_type=std_logic lab=VCM}
C {lab_pin.sym} 40 -1460 0 0 {name=p366 sig_type=std_logic lab=CLK2}
C {lab_pin.sym} 40 -1760 0 0 {name=p367 sig_type=std_logic lab=CLK2_b}
C {pfet_03v3.sym} 40 -1300 1 0 {name=M59
L=0.18u
W=5.4u
nf=1
m=1
ad="'int((nf+1)/2) * W/nf * 0.18u'"
pd="'2*int((nf+1)/2) * (W/nf + 0.18u)'"
as="'int((nf+2)/2) * W/nf * 0.18u'"
ps="'2*int((nf+2)/2) * (W/nf + 0.18u)'"
nrd="'0.18u / W'" nrs="'0.18u / W'"
sa=0 sb=0 sd=0
model=pfet_03v3
spiceprefix=X
}
C {nfet_03v3.sym} 40 -1080 3 0 {name=M60
L=0.18u
W=1.8u
nf=1
m=1
ad="'int((nf+1)/2) * W/nf * 0.18u'"
pd="'2*int((nf+1)/2) * (W/nf + 0.18u)'"
as="'int((nf+2)/2) * W/nf * 0.18u'"
ps="'2*int((nf+2)/2) * (W/nf + 0.18u)'"
nrd="'0.18u / W'" nrs="'0.18u / W'"
sa=0 sb=0 sd=0
model=nfet_03v3
spiceprefix=X
}
C {lab_pin.sym} 40 -1250 0 0 {name=p368 sig_type=std_logic lab=avdd}
C {lab_pin.sym} 40 -1130 0 0 {name=p369 sig_type=std_logic lab=agnd}
C {lab_pin.sym} -20 -1190 0 0 {name=p370 sig_type=std_logic lab=VCM}
C {lab_pin.sym} 40 -1040 0 0 {name=p371 sig_type=std_logic lab=CLK2}
C {lab_pin.sym} 40 -1340 0 0 {name=p372 sig_type=std_logic lab=CLK2_b}
C {pfet_03v3.sym} 1240 -1840 0 0 {name=M61
L=0.18u
W=3.6u
nf=1
m=1
ad="'int((nf+1)/2) * W/nf * 0.18u'"
pd="'2*int((nf+1)/2) * (W/nf + 0.18u)'"
as="'int((nf+2)/2) * W/nf * 0.18u'"
ps="'2*int((nf+2)/2) * (W/nf + 0.18u)'"
nrd="'0.18u / W'" nrs="'0.18u / W'"
sa=0 sb=0 sd=0
model=pfet_03v3
spiceprefix=X
}
C {nfet_03v3.sym} 1240 -1710 0 0 {name=M62
L=0.18u
W=1.8u
nf=1
m=1
ad="'int((nf+1)/2) * W/nf * 0.18u'"
pd="'2*int((nf+1)/2) * (W/nf + 0.18u)'"
as="'int((nf+2)/2) * W/nf * 0.18u'"
ps="'2*int((nf+2)/2) * (W/nf + 0.18u)'"
nrd="'0.18u / W'" nrs="'0.18u / W'"
sa=0 sb=0 sd=0
model=nfet_03v3
spiceprefix=X
}
C {lab_pin.sym} 1260 -1900 0 0 {name=p373 sig_type=std_logic lab=avdd}
C {lab_pin.sym} 1260 -1660 0 0 {name=p374 sig_type=std_logic lab=agnd}
C {lab_pin.sym} 1190 -1780 0 0 {name=p375 sig_type=std_logic lab=CLK2D}
C {lab_pin.sym} 1290 -1780 0 0 {name=p376 sig_type=std_logic lab=CLK2D_b}
C {pfet_03v3.sym} 1520 -1840 0 0 {name=M63
L=0.18u
W=3.6u
nf=1
m=1
ad="'int((nf+1)/2) * W/nf * 0.18u'"
pd="'2*int((nf+1)/2) * (W/nf + 0.18u)'"
as="'int((nf+2)/2) * W/nf * 0.18u'"
ps="'2*int((nf+2)/2) * (W/nf + 0.18u)'"
nrd="'0.18u / W'" nrs="'0.18u / W'"
sa=0 sb=0 sd=0
model=pfet_03v3
spiceprefix=X
}
C {nfet_03v3.sym} 1520 -1710 0 0 {name=M64
L=0.18u
W=1.8u
nf=1
m=1
ad="'int((nf+1)/2) * W/nf * 0.18u'"
pd="'2*int((nf+1)/2) * (W/nf + 0.18u)'"
as="'int((nf+2)/2) * W/nf * 0.18u'"
ps="'2*int((nf+2)/2) * (W/nf + 0.18u)'"
nrd="'0.18u / W'" nrs="'0.18u / W'"
sa=0 sb=0 sd=0
model=nfet_03v3
spiceprefix=X
}
C {lab_pin.sym} 1540 -1900 0 0 {name=p377 sig_type=std_logic lab=avdd}
C {lab_pin.sym} 1540 -1660 0 0 {name=p378 sig_type=std_logic lab=agnd}
C {lab_pin.sym} 1470 -1780 0 0 {name=p379 sig_type=std_logic lab=CLK2}
C {lab_pin.sym} 1570 -1780 0 0 {name=p380 sig_type=std_logic lab=CLK2_b}
C {SARlogic.sym} 1970 260 0 0 {name=x15}
C {lab_pin.sym} 2140 30 0 0 {name=p381 sig_type=std_logic lab=CLK<0>}
C {lab_pin.sym} 2140 50 0 0 {name=p382 sig_type=std_logic lab=CLKR<0>}
C {lab_pin.sym} 2140 70 0 0 {name=p383 sig_type=std_logic lab=CLKR<1>}
C {lab_pin.sym} 2140 90 0 0 {name=p384 sig_type=std_logic lab=CLK<1>}
C {lab_pin.sym} 2140 110 0 0 {name=p385 sig_type=std_logic lab=CLKR<2>}
C {lab_pin.sym} 2140 130 0 0 {name=p386 sig_type=std_logic lab=CLK<2>}
C {lab_pin.sym} 2140 170 0 0 {name=p388 sig_type=std_logic lab=CLK<3>}
C {lab_pin.sym} 2140 150 0 0 {name=p387 sig_type=std_logic lab=CLKR<3>}
C {lab_pin.sym} 2140 190 0 0 {name=p389 sig_type=std_logic lab=CLKR<4>}
C {lab_pin.sym} 2140 210 0 0 {name=p390 sig_type=std_logic lab=CLK<4>}
C {lab_pin.sym} 2140 230 0 0 {name=p391 sig_type=std_logic lab=CLKR<5>}
C {lab_pin.sym} 2140 250 0 0 {name=p392 sig_type=std_logic lab=CLK<5>}
C {lab_pin.sym} 2140 270 0 0 {name=p393 sig_type=std_logic lab=CLKR<6>}
C {lab_pin.sym} 2140 290 0 0 {name=p394 sig_type=std_logic lab=CLK<6>}
C {lab_pin.sym} 2140 310 0 0 {name=p395 sig_type=std_logic lab=CLKR<7>}
C {lab_pin.sym} 2140 330 0 0 {name=p396 sig_type=std_logic lab=CLK<7>}
C {lab_pin.sym} 2140 350 0 0 {name=p397 sig_type=std_logic lab=CLKR<8>}
C {lab_pin.sym} 2140 370 0 0 {name=p398 sig_type=std_logic lab=CLK<8>}
C {lab_pin.sym} 2140 390 0 0 {name=p399 sig_type=std_logic lab=CLKR<9>}
C {lab_pin.sym} 2140 410 0 0 {name=p400 sig_type=std_logic lab=CLK<9>}
C {lab_pin.sym} 2140 430 0 0 {name=p401 sig_type=std_logic lab=CLKR<10>}
C {lab_pin.sym} 2140 450 0 0 {name=p402 sig_type=std_logic lab=CLK<10>}
C {lab_pin.sym} 2140 470 0 0 {name=p403 sig_type=std_logic lab=CLK<11>}
C {lab_pin.sym} 2140 490 0 0 {name=p404 sig_type=std_logic lab=CLKR<11>}
C {lab_pin.sym} 2140 510 0 0 {name=p405 sig_type=std_logic lab=CLKR<12>}
C {lab_pin.sym} 2140 530 0 0 {name=p406 sig_type=std_logic lab=CLK<12>}
C {lab_pin.sym} 2140 550 0 0 {name=p407 sig_type=std_logic lab=CLK<13>}
C {iopin.sym} -760 -1470 0 0 {name=p409 lab=agnd}
C {ipin.sym} -870 -1500 0 0 {name=p410 lab=CLK1D}
C {iopin.sym} -760 -1510 0 0 {name=p412 lab=avdd}
C {iopin.sym} -760 -1420 0 0 {name=p413 lab=VCM}
C {iopin.sym} -670 -1470 0 0 {name=p414 lab=REFP}
C {iopin.sym} -670 -1510 0 0 {name=p415 lab=REFN}
C {ipin.sym} -870 -1460 0 0 {name=p416 lab=CLK2D}
C {opin.sym} -490 -1510 0 0 {name=p417 lab=B<0>}
C {ipin.sym} -870 -1420 0 0 {name=p418 lab=CLK2}
C {opin.sym} -490 -1470 0 0 {name=p411 lab=B<1>}
C {opin.sym} -490 -1440 0 0 {name=p419 lab=B<3>}
C {opin.sym} -490 -1400 0 0 {name=p420 lab=B<4>}
C {opin.sym} -490 -1370 0 0 {name=p421 lab=B<5>}
C {opin.sym} -490 -1330 0 0 {name=p422 lab=B<6>}
C {opin.sym} -490 -1300 0 0 {name=p423 lab=B<7>}
C {opin.sym} -490 -1260 0 0 {name=p424 lab=B<8>}
C {opin.sym} -490 -1230 0 0 {name=p425 lab=B<9>}
C {opin.sym} -490 -1190 0 0 {name=p426 lab=B<10>}
C {opin.sym} -490 -1160 0 0 {name=p427 lab=B<11>}
C {opin.sym} -490 -1120 0 0 {name=p428 lab=B<12>}
C {opin.sym} -490 -1090 0 0 {name=p429 lab=B<13>}
C {opin.sym} -490 -1050 0 0 {name=p430 lab=B<2>}
C {ipin.sym} -960 -1500 0 0 {name=p457 lab=VIN}
C {ipin.sym} -960 -1460 0 0 {name=p458 lab=VIP}
C {/home/yihengfu/openmpw/tools-dev/LSB_N.sym} 970 -1470 0 0 {name=x37}
C {/home/yihengfu/openmpw/tools-dev/LSB_P.sym} 970 -1230 0 0 {name=x38}
C {/home/yihengfu/openmpw/tools-dev/MSB_N.sym} 520 -1470 0 0 {name=x39}
C {/home/yihengfu/openmpw/tools-dev/MSB_P.sym} 530 -1230 0 0 {name=x40}
C {lab_pin.sym} 690 -1520 0 0 {name=p223 sig_type=std_logic lab=vgateN}
C {lab_pin.sym} 690 -1500 0 0 {name=p224 sig_type=std_logic lab=VCM}
C {lab_pin.sym} 690 -1480 0 0 {name=p225 sig_type=std_logic lab=agnd}
C {lab_pin.sym} 690 -1460 0 0 {name=p226 sig_type=std_logic lab=CLK[0:7]}
C {lab_pin.sym} 680 -1440 0 0 {name=p227 sig_type=std_logic lab=VIN}
C {lab_pin.sym} 690 -1420 0 0 {name=p228 sig_type=std_logic lab=CLK1D}
C {lab_pin.sym} 700 -1280 0 0 {name=p229 sig_type=std_logic lab=vgateP}
C {lab_pin.sym} 700 -1260 0 0 {name=p230 sig_type=std_logic lab=VCM}
C {lab_pin.sym} 700 -1240 0 0 {name=p231 sig_type=std_logic lab=agnd}
C {lab_pin.sym} 700 -1220 0 0 {name=p232 sig_type=std_logic lab=CLK[0:7]}
C {lab_pin.sym} 690 -1200 0 0 {name=p233 sig_type=std_logic lab=VIP}
C {lab_pin.sym} 700 -1180 0 0 {name=p234 sig_type=std_logic lab=CLK1D}
C {lab_pin.sym} 1140 -1280 0 0 {name=p235 sig_type=std_logic lab=vgateP}
C {lab_pin.sym} 1140 -1260 0 0 {name=p236 sig_type=std_logic lab=VCM}
C {lab_pin.sym} 1140 -1240 0 0 {name=p237 sig_type=std_logic lab=agnd}
C {lab_pin.sym} 1140 -1220 0 0 {name=p238 sig_type=std_logic lab=CLK[8:12]}
C {lab_pin.sym} 1130 -1200 0 0 {name=p239 sig_type=std_logic lab=VIP}
C {lab_pin.sym} 1140 -1180 0 0 {name=p240 sig_type=std_logic lab=CLK1D}
C {lab_pin.sym} 1140 -1520 0 0 {name=p241 sig_type=std_logic lab=vgateN}
C {lab_pin.sym} 1140 -1500 0 0 {name=p242 sig_type=std_logic lab=VCM}
C {lab_pin.sym} 1140 -1480 0 0 {name=p243 sig_type=std_logic lab=agnd}
C {lab_pin.sym} 1140 -1460 0 0 {name=p244 sig_type=std_logic lab=CLK[8:12]}
C {lab_pin.sym} 1130 -1440 0 0 {name=p245 sig_type=std_logic lab=VIN}
C {lab_pin.sym} 1140 -1420 0 0 {name=p246 sig_type=std_logic lab=CLK1D}
C {/home/yihengfu/openmpw/tools-dev/cap_mim_2p0fF.sym} 560 -1600 3 0 {name=C1
W=1e-6
L=1e-6
model=cap_mim_2p0fF
spiceprefix=X
m=1}
C {/home/yihengfu/openmpw/Project-Futo-Chip1/xschem/gf180mcu_fd_pr/cap_mim_2p0fF.sym} 560 -1050 3 0 {name=C2
W=1e-6
L=1e-6
model=cap_mim_2p0fF
spiceprefix=X
m=1}
